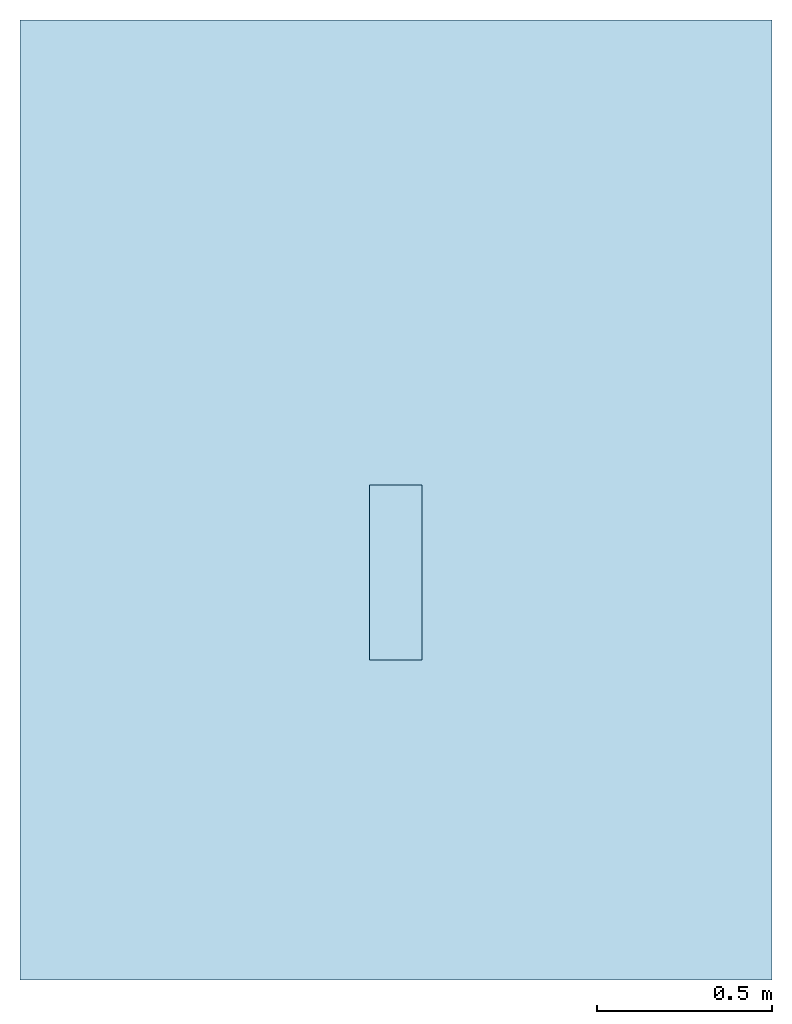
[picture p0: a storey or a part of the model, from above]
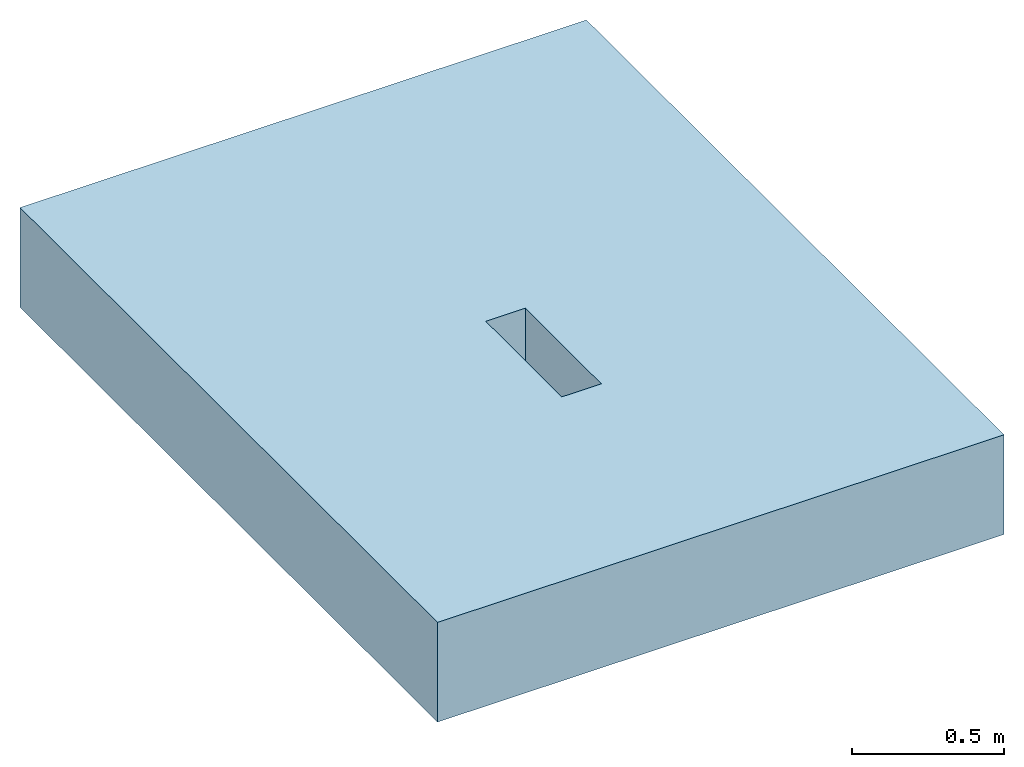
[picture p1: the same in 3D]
Properties of the parts of a building model (IFC2X3)

# File
Description: ViewDefinition [CoordinationView]
File name: 4926 - KDHB480 Channel - 500mm LG.ifc
Time: 2013-09-18T16:20:59
Written by: Autodesk Revit 2013
Made in: 20120221_2030(x64)

# IfcProject, Project Number
LongName: Project Name; Phase: Project Status

# IfcSite, Default
RefLatitude: 42, 21, 30, 344238; RefLongitude: -71, -3, -35, -194702; RefElevation: 0 mm

# IfcBuilding
Pset_BuildingCommon - NumberOfStoreys: 2
Other - Project Name: Project Name; Project Number: Project Number; Project Status: Project Status; Project Issue Date: Issue Date; Project Address: Enter address here; Client Name: Owner

# IfcBuildingStorey (2)
Constraints - Elevation Base: 0
Graphics - Line Pattern: Center; Symbol at End 1 Default: no; Symbol: M_Level Head - Circle: M_Level Head - Circle; Symbol at End 2 Default: yes; Color: 0; Line Weight: 1
Dimensions - Computation Height: 0 mm
Identity Data - Building Story: yes; Structural: no
Name | LongName = Name | Elevation (mm) = Constraints, Elevation (mm)
T.O. Fnd. Wall | T.O. Fnd. Wall | -300
Level 1 | Level 1 | 0

# IfcBuildingElementProxy: 4926 - KDHB480 Channel - 500mm LG, Civil-Drainage-Channel-ACO-KerbDrain-HB480(amar):4926 - KDHB480 Channel - 500mm LG:4926 - KDHB480 Channel - 500mm LG:481515
In: T.O. Fnd. Wall
Material: ACO Polymer Concrete.
Other - Revision: 1; CreatedBy: www.aco.co.uk
Identity Data - Fax: +44 (0)1462 815895; Model Description: Combined kerb and drainage system; OmniClass Title: Rainwater Removal; Maintenance guidelines: http://www.aco.co.uk/download.php?id=120; Assembly Description: Rain Water Drainage; Cost: 0; Installation guidelines: http://www.aco.co.uk/download.php?id=120; e-mail Technical: technical@aco.co.uk; Product brochure: http://www.aco.co.uk/download.php?id=120; e-mail Sales: customersupport@aco.co.uk; Address: ACO Business Park, Hitchin Road, Shefford, Bedfordshire, United Kingdom SG17 5TE; URL: www.aco.co.uk; Telephone: +44 (0)1462 816666; OmniClass Number: 23.70.50.24; Type Comments: ACO KerbDrain HB480 half battered RH outlet end cap; Product Code: 4940; Manufacturer: ACO Technologies plc - ACO Water Management Division; Product Page URL: http://www.aco.co.uk/product_detail.php?id=3; Assembly Code: D2040; Price: POA - contact ACO; Model: ACO KerbDrain HB480
Constraints - Moves With Nearby Elements: no; Level: Level: Level 1
Phasing - Phase Created: Phase 1
Dimensions - Volume: 16814393 mm3; junction void depth: 2000 mm; Mitre Small End: 487 mm; Junction Start: 0 mm; Mitre Void Start: -4565 mm; Void Start I/O: -5.1 mm; I/O endcap void depth: 2500 mm; Void Depth: -355 mm; Mitre Void End: -4570 mm; Mitre Long end: 500 mm; Junction End: 2 mm; Void End I/O: 155.1 mm; Void Length: 500 mm; Void Width: 150 mm; Straight Void Start: 0 mm
Pset_BuildingElementProxyCommon - Reference: 4926 - KDHB480 Channel - 500mm LG
Construction - RH drop kerb: no; HB480-500: yes; RH BS transition kerb: no; Junction channel: no; perforated centre stone: no; 25-11m external mitre: no; RH inlet/outlet end cap: no; LH BS transition kerb: no; Junction access unit: no; LH inlet/outlet end cap: no; LH drop kerb: no; Access Unit: no; KDHB480 500_blindunit: no; Centre Stone: no; Closing end cap: no; Junction end cap: no; cable loop: no; 25-11m internal mitre: no; 10-8m external mitre: no; 7-6m external mitre: no; Bus stop kerb: no
Green Building Properties - End Cap Recyclable: Fully recyclable; Channel Recyclable: N/A; Access Cover/Frame Recyclable: N/A; End Cap Recycled Material Content: 20% minimum; Channel Recycled Material Content: N/A; Access Cover/Frame Recycled Material Content: N/A
Data - Product Weight: 5.9 Kg; Product Standard: N/A; Concrete Surround Volume - Load Class A 15 - D 400 - Concrete Pavement: N/A; Product Dimensions: 50mm x 150mm x 480mm (LxWxH); Installation - Concrete Grade: N/A; Connection Pipe O.D: Ø160mm; Channel C.S.A: N/A; Invert Depth: N/A; Drainage Slot Width: N/A; Hydraulic Performance: N/A; Drainage Slot Intake area: N/A; Concrete Surround Volume - Load Class A 15 - D 400 - Grass or Asphalt Pavement: N/A; Load Class: N/A; ACO Hydraulic Design Software: N/A
Materials and Finishes - Connection Pipe Material Colour: Black; Channel Colour: N/A; Access Cover/Frame Finish: N/A; End Cap Material: Vienite® Synthetic Resin Concrete; Connection Pipe Material: Medium Density Polyethylene; End Cap Colour: Grey; Channel Material: N/A; Access Cover/Frame Colour: N/A; Access Cover/Frame Material: N/A
General - TagNumber: 0.000000; SerialNumber: 0.000000

# IfcOpeningElement: Opening (4)
In: Level 1
Dimensions - Thickness: 400 mm; Area: 5901750 mm2; Perimeter: 9790 mm; Volume: 2334075000 mm3
Structural - Enable Analytical Model: no; Structural: no
Constraints - Related to Mass: no; Height Offset From Level: 0 mm; Level: Level: Level 1; Room Bounding: yes
Phasing - Phase Created: Phase 1
Materials and Finishes - Structural Material: Earth
Construction - Function: 0; Default Thickness: 400 mm
Graphics - Coarse Scale Fill Color: 0
Analytical Properties - Roughness: 1; Thermal mass: 543920; Absorptance: 0.1; Heat Transfer Coefficient (U): 2.0925; Thermal Resistance (R): 0.477897

# IfcSlab: Floor:Generic Floor - 400mm, Floor:Generic Floor - 400mm:136426
In: Level 1
PredefinedType: FLOOR; Material: Earth 400 mm
Dimensions - Thickness: 400 mm; Area: 5901750 mm2; Perimeter: 9790 mm; Volume: 2334075000 mm3
Structural - Enable Analytical Model: no; Structural: no
Constraints - Related to Mass: no; Height Offset From Level: 0 mm; Level: Level: Level 1; Room Bounding: yes
Phasing - Phase Created: Phase 1
Pset_SlabCommon - Reference: Generic Floor - 400mm; IsExternal: no; LoadBearing: yes
Materials and Finishes - Structural Material: Earth
Construction - Function: 0; Default Thickness: 400 mm
Graphics - Coarse Scale Fill Color: 0
Analytical Properties - Roughness: 1; Thermal mass: 543920; Absorptance: 0.1; Heat Transfer Coefficient (U): 2.0925; Thermal Resistance (R): 0.477897
